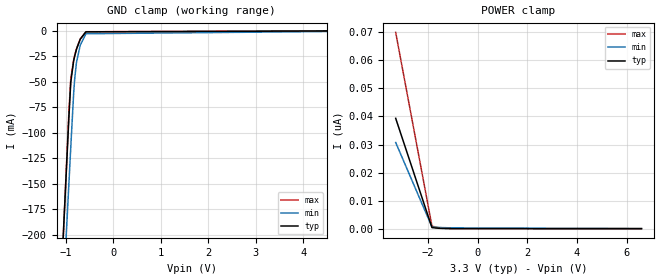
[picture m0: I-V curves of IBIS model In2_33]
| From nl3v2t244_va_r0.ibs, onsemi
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|//////////////////////////////////////////////////////////////////////////////
|//////////////////////////////////////////////////////////////////////////////
[Model]  In2_33
Model_type Input
Vinh = 2.00
Vinl = 0.80
|  variable   typ   min   max
C_comp   4.8pF   4.8pF   4.8pF
|//////////////////////////////////////////////////////////////////////////////
[Temperature Range]   25   125   -40
|//////////////////////////////////////////////////////////////////////////////
[Voltage Range]   3.30V   3.00V   3.60V
|//////////////////////////////////////////////////////////////////////////////
[POWER Clamp Reference] 3.30V   3.00V   3.60V
|//////////////////////////////////////////////////////////////////////////////
[GND Clamp Reference]   0V   0V   0V
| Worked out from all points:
|   GND clamp passes 1 mA (typ) near -0.57 V on its own axis
|//////////////////////////////////////////////////////////////////////////////
[GND Clamp]
|   Voltage   I(typ)   I(min)   I(max)
-3.3V     -2.383A    -2.276A    -2.511A
-1.14V    -280.4mA   -330.5mA   -286.4mA
-1.08V    -222mA     -276.5mA   -224.6mA
-1.02V    -163.6mA   -222.4mA   -162.8mA
-940mV    -85.69mA   -150.4mA   -80.36mA
-900mV    -50.76mA   -114.4mA   -47.48mA
-840mV    -29.83mA   -62.34mA   -28.98mA
-820mV    -25.58mA   -48.77mA   -24.83mA
-780mV    -18.41mA   -31.28mA   -17.89mA
-700mV    -8.441mA   -14.21mA   -8.172mA
-580mV    -1.228mA   -3.078mA   -1.128mA
6.6V      4.624pA    275.1pA    1.764pA
|//////////////////////////////////////////////////////////////////////////////
[POWER Clamp]
|   Voltage   I(typ)   I(min)   I(max)
-3.3V     39.34nA    30.71nA    69.98nA
-1.84V    398.8pA    634.8pA    957.7pA
-1.8V     344.2pA    593.6pA    828pA
-1.68V    215pA      495.8pA    534pA
-1.6V     158.9pA    448.6pA    394.7pA
-1.56V    136.4pA    430.5pA    346.7pA
-1.44V    84.2pA     381.4pA    210.6pA
-1.32V    55.68pA    343.7pA    130.8pA
-1.16V    29.6pA     306.6pA    69.4pA
-920mV    10.88pA    269pA      26.52pA
300mV     1.744pA    183.2pA    973.3fA
6.6V      -3.296pA   18.49pA    -537fA
